VERSION 5.8 ;
BUSBITCHARS "[]" ;
DIVIDERCHAR "/" ;

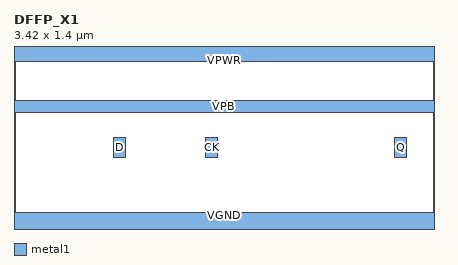
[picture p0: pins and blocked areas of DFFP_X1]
MACRO DFFP_X1
  CLASS CORE ; ORIGIN 0 0 ; FOREIGN DFFP_X1 0 0 ; SIZE 3.42 BY 1.4 ; SYMMETRY X Y ; SITE FreePDK45_38x28_10R_NP_162NW_34O ;
  PIN D DIRECTION INPUT ; USE SIGNAL ; PORT LAYER metal1 ; RECT 0.81 0.53 0.91 0.7 ; END END D
  PIN CK DIRECTION INPUT ; USE SIGNAL ; PORT LAYER metal1 ; RECT 1.56 0.53 1.66 0.7 ; END END CK
  PIN Q DIRECTION OUTPUT ; USE SIGNAL ; PORT LAYER metal1 ; RECT 3.10 0.53 3.20 0.7 ; END END Q
  PIN VPWR DIRECTION INOUT ; USE POWER ; SHAPE ABUTMENT ; PORT LAYER metal1 ; RECT 0 1.315 3.42 1.485 ; END END VPWR
  PIN VPB DIRECTION INOUT ; USE POWER ; SHAPE ABUTMENT ; PORT LAYER metal1 ; RECT 0 0.900 3.42 1.000 ; END END VPB
  PIN VGND DIRECTION INOUT ; USE GROUND ; SHAPE ABUTMENT ; PORT LAYER metal1 ; RECT 0 -0.085 3.42 0.085 ; END END VGND
END DFFP_X1

END LIBRARY
